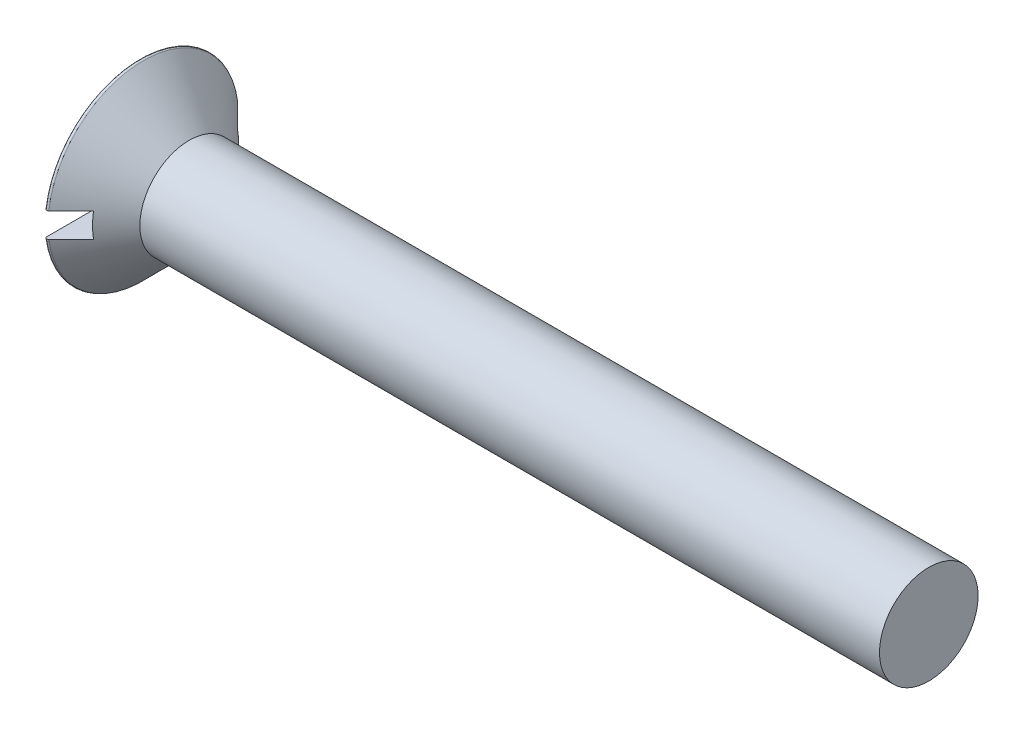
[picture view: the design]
ISO-10303-21;
HEADER;
FILE_DESCRIPTION(('STEP AP214'),'2;1');
FILE_NAME('part.step','',(''),(''),'','','');
FILE_SCHEMA(('AUTOMOTIVE_DESIGN { 1 0 10303 214 1 1 1 1 }'));
ENDSEC;
DATA;
#1=APPLICATION_CONTEXT('core data for automotive mechanical design processes');
#2=APPLICATION_PROTOCOL_DEFINITION('international standard','automotive_design',2000,#1);
#3=PRODUCT_CONTEXT('',#1,'mechanical');
#4=PRODUCT('Part','Part','',(#3));
#5=PRODUCT_RELATED_PRODUCT_CATEGORY('part','',(#4));
#6=PRODUCT_DEFINITION_FORMATION('','',#4);
#7=PRODUCT_DEFINITION_CONTEXT('part definition',#1,'design');
#8=PRODUCT_DEFINITION('design','',#6,#7);
#9=PRODUCT_DEFINITION_SHAPE('','',#8);
#10=(LENGTH_UNIT() NAMED_UNIT(*) SI_UNIT(.MILLI.,.METRE.));
#11=(NAMED_UNIT(*) PLANE_ANGLE_UNIT() SI_UNIT($,.RADIAN.));
#12=(NAMED_UNIT(*) SI_UNIT($,.STERADIAN.) SOLID_ANGLE_UNIT());
#13=UNCERTAINTY_MEASURE_WITH_UNIT(LENGTH_MEASURE(1.E-05),#10,'distance_accuracy_value','');
#14=(GEOMETRIC_REPRESENTATION_CONTEXT(3) GLOBAL_UNCERTAINTY_ASSIGNED_CONTEXT((#13)) GLOBAL_UNIT_ASSIGNED_CONTEXT((#10,
#11,#12)) REPRESENTATION_CONTEXT('',''));
#15=CARTESIAN_POINT('',(0.,0.,0.));
#16=DIRECTION('',(0.,0.,1.));
#17=DIRECTION('',(1.,0.,0.));
#18=AXIS2_PLACEMENT_3D('',#15,#16,#17);
#19=CARTESIAN_POINT('',(0.,0.,0.));
#20=DIRECTION('',(1.,0.,0.));
#21=DIRECTION('',(0.,0.,-1.));
#22=AXIS2_PLACEMENT_3D('',#19,#20,#21);
#23=PLANE('',#22);
#24=CARTESIAN_POINT('',(0.,0.,0.));
#25=DIRECTION('',(1.,0.,0.));
#26=DIRECTION('',(0.,0.,-1.));
#27=AXIS2_PLACEMENT_3D('',#24,#25,#26);
#28=CIRCLE('',#27,9.51715728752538);
#29=CARTESIAN_POINT('',(0.,1.25,9.4347115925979));
#30=VERTEX_POINT('',#29);
#31=CARTESIAN_POINT('',(0.,1.25,-9.43471159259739));
#32=VERTEX_POINT('',#31);
#33=EDGE_CURVE('E177',#30,#32,#28,.F.);
#34=ORIENTED_EDGE('',*,*,#33,.T.);
#35=DIRECTION('',(0.,0.,1.));
#36=VECTOR('',#35,1.);
#37=CARTESIAN_POINT('',(0.,1.25,-9.71715728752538));
#38=LINE('',#37,#36);
#39=EDGE_CURVE('E114',#32,#30,#38,.T.);
#40=ORIENTED_EDGE('',*,*,#39,.T.);
#41=EDGE_LOOP('',(#34,#40));
#42=FACE_BOUND('',#41,.T.);
#43=ADVANCED_FACE('F36',(#42),#23,.F.);
#44=CARTESIAN_POINT('',(0.2,0.,0.));
#45=DIRECTION('',(1.,0.,0.));
#46=DIRECTION('',(0.,0.,-1.));
#47=AXIS2_PLACEMENT_3D('',#44,#45,#46);
#48=TOROIDAL_SURFACE('',#47,9.51715728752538,0.2);
#49=CARTESIAN_POINT('',(0.0813932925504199,1.25,-9.59713064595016));
#50=CARTESIAN_POINT('',(0.090371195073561,1.25,-9.60379834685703));
#51=CARTESIAN_POINT('',(0.0999156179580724,1.25,-9.60971625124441));
#52=CARTESIAN_POINT('',(0.119869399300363,1.25,-9.61987230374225));
#53=CARTESIAN_POINT('',(0.130279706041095,1.25,-9.62410858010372));
#54=CARTESIAN_POINT('',(0.15166318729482,1.25,-9.63076900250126));
#55=CARTESIAN_POINT('',(0.162636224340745,1.25,-9.63319358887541));
#56=CARTESIAN_POINT('',(0.184831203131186,1.25,-9.63615852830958));
#57=CARTESIAN_POINT('',(0.196053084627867,1.25,-9.63669933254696));
#58=CARTESIAN_POINT('',(0.218392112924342,1.25,-9.63588331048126));
#59=CARTESIAN_POINT('',(0.229509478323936,1.25,-9.63453245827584));
#60=CARTESIAN_POINT('',(0.251359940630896,1.25,-9.62998393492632));
#61=CARTESIAN_POINT('',(0.262093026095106,1.25,-9.62678620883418));
#62=CARTESIAN_POINT('',(0.282875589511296,1.25,-9.61863708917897));
#63=CARTESIAN_POINT('',(0.292924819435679,1.25,-9.61368506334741));
#64=CARTESIAN_POINT('',(0.312055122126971,1.25,-9.60217267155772));
#65=CARTESIAN_POINT('',(0.321136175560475,1.25,-9.59561227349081));
#66=CARTESIAN_POINT('',(0.338125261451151,1.25,-9.58103410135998));
#67=CARTESIAN_POINT('',(0.34602683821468,1.25,-9.57300880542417));
#68=CARTESIAN_POINT('',(0.360383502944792,1.25,-9.55575484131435));
#69=CARTESIAN_POINT('',(0.36683853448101,1.25,-9.54652612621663));
#70=CARTESIAN_POINT('',(0.378174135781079,1.25,-9.52704814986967));
#71=CARTESIAN_POINT('',(0.383041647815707,1.25,-9.51679128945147));
#72=CARTESIAN_POINT('',(0.391000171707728,1.25,-9.49561008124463));
#73=CARTESIAN_POINT('',(0.394091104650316,1.25,-9.48468570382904));
#74=CARTESIAN_POINT('',(0.398430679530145,1.25,-9.46239224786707));
#75=CARTESIAN_POINT('',(0.399665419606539,1.25,-9.45102046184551));
#76=CARTESIAN_POINT('',(0.400215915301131,1.25,-9.42823040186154));
#77=CARTESIAN_POINT('',(0.399531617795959,1.25,-9.41681212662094));
#78=CARTESIAN_POINT('',(0.396256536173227,1.25,-9.39420937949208));
#79=CARTESIAN_POINT('',(0.393658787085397,1.25,-9.38302591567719));
#80=CARTESIAN_POINT('',(0.386619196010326,1.25,-9.36125501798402));
#81=CARTESIAN_POINT('',(0.382177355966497,1.25,-9.35066758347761));
#82=CARTESIAN_POINT('',(0.371581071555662,1.25,-9.3304129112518));
#83=CARTESIAN_POINT('',(0.365429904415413,1.25,-9.32074395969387));
#84=CARTESIAN_POINT('',(0.35158114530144,1.25,-9.30258514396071));
#85=CARTESIAN_POINT('',(0.343883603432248,1.25,-9.29409524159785));
#86=CARTESIAN_POINT('',(0.327215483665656,1.25,-9.2785990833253));
#87=CARTESIAN_POINT('',(0.318253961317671,1.25,-9.27158308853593));
#88=CARTESIAN_POINT('',(0.299271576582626,1.25,-9.25917099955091));
#89=CARTESIAN_POINT('',(0.289250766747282,1.25,-9.25377482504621));
#90=CARTESIAN_POINT('',(0.268528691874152,1.25,-9.24480504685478));
#91=CARTESIAN_POINT('',(0.257834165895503,1.25,-9.24121587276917));
#92=CARTESIAN_POINT('',(0.235992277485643,1.25,-9.23589752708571));
#93=CARTESIAN_POINT('',(0.224844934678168,1.25,-9.23416827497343));
#94=CARTESIAN_POINT('',(0.202493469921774,1.25,-9.23262729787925));
#95=CARTESIAN_POINT('',(0.191290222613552,1.25,-9.2328028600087));
#96=CARTESIAN_POINT('',(0.169072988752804,1.25,-9.23503550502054));
#97=CARTESIAN_POINT('',(0.158058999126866,1.25,-9.23709255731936));
#98=CARTESIAN_POINT('',(0.136548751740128,1.25,-9.24302213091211));
#99=CARTESIAN_POINT('',(0.126051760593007,1.25,-9.24689199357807));
#100=CARTESIAN_POINT('',(0.105852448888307,1.25,-9.25633161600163));
#101=CARTESIAN_POINT('',(0.096150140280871,1.25,-9.26190140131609));
#102=CARTESIAN_POINT('',(0.0777682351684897,1.25,-9.27460622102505));
#103=CARTESIAN_POINT('',(0.0690933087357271,1.25,-9.28174801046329));
#104=CARTESIAN_POINT('',(0.0530534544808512,1.25,-9.2973758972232));
#105=CARTESIAN_POINT('',(0.0456885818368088,1.25,-9.30586205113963));
#106=CARTESIAN_POINT('',(0.0324133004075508,1.25,-9.32401149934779));
#107=CARTESIAN_POINT('',(0.026515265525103,1.25,-9.33368384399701));
#108=CARTESIAN_POINT('',(0.016411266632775,1.25,-9.35387523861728));
#109=CARTESIAN_POINT('',(0.0122053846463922,1.25,-9.36439432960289));
#110=CARTESIAN_POINT('',(0.00557032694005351,1.25,-9.38607414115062));
#111=CARTESIAN_POINT('',(0.00315614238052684,1.25,-9.39723945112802));
#112=CARTESIAN_POINT('',(0.000226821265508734,1.25,-9.41981615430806));
#113=CARTESIAN_POINT('',(-0.000288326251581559,1.25,-9.43122754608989));
#114=CARTESIAN_POINT('',(0.000596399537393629,1.25,-9.45402874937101));
#115=CARTESIAN_POINT('',(0.00200510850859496,1.25,-9.46541821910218));
#116=CARTESIAN_POINT('',(0.00671661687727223,1.25,-9.48780185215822));
#117=CARTESIAN_POINT('',(0.010019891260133,1.25,-9.49879591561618));
#118=CARTESIAN_POINT('',(0.0184290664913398,1.25,-9.5200665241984));
#119=CARTESIAN_POINT('',(0.0235343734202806,1.25,-9.53034330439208));
#120=CARTESIAN_POINT('',(0.0354046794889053,1.25,-9.54987753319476));
#121=CARTESIAN_POINT('',(0.042167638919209,1.25,-9.5591362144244));
#122=CARTESIAN_POINT('',(0.0544013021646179,1.25,-9.57319981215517));
#123=CARTESIAN_POINT('',(0.0594345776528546,1.25,-9.57839171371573));
#124=CARTESIAN_POINT('',(0.0700308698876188,1.25,-9.58820358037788));
#125=CARTESIAN_POINT('',(0.0755938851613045,1.25,-9.59282354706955));
#126=CARTESIAN_POINT('',(0.0813932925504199,1.25,-9.59713064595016));
#127=B_SPLINE_CURVE_WITH_KNOTS('',3,(#49,#50,#51,#52,#53,#54,#55,#56,#57,#58,#59,#60,#61,#62,
#63,#64,#65,#66,#67,#68,#69,#70,#71,#72,#73,#74,#75,#76,#77,#78,#79,#80,#81,#82,#83,#84,#85,#86,
#87,#88,#89,#90,#91,#92,#93,#94,#95,#96,#97,#98,#99,#100,#101,#102,#103,#104,#105,#106,#107,
#108,#109,#110,#111,#112,#113,#114,#115,#116,#117,#118,#119,#120,#121,#122,#123,#124,#125,#126),
.UNSPECIFIED.,.T.,.F.,(4,2,2,2,2,2,2,2,2,2,2,2,2,2,2,2,2,2,2,2,2,2,2,2,2,2,2,2,2,2,2,2,2,2,2,2,
2,2,4),(0.,0.033523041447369,0.0670832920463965,0.100635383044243,0.134179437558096,
0.167617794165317,0.201057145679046,0.234508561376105,0.267960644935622,0.301589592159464,
0.335219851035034,0.369120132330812,0.40302191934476,0.437176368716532,0.471331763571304,
0.505612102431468,0.539892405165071,0.57410743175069,0.608321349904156,0.64230154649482,
0.676280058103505,0.70996054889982,0.74363958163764,0.777093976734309,0.810547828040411,
0.843952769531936,0.877358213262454,0.910910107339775,0.944463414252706,0.978290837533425,
1.01211990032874,1.04622891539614,1.08033773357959,1.11460373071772,1.14887832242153,
1.18314162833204,1.217362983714,1.23901774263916,1.26067244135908),.UNSPECIFIED.);
#128=CARTESIAN_POINT('',(0.341421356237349,1.25,-9.57735043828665));
#129=VERTEX_POINT('',#128);
#130=EDGE_CURVE('E60',#32,#129,#127,.T.);
#131=ORIENTED_EDGE('',*,*,#130,.F.);
#132=ORIENTED_EDGE('',*,*,#33,.F.);
#133=CARTESIAN_POINT('',(0.0799210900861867,1.25,9.27334894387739));
#134=CARTESIAN_POINT('',(0.0888343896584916,1.25,9.26659717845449));
#135=CARTESIAN_POINT('',(0.0983208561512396,1.25,9.26058928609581));
#136=CARTESIAN_POINT('',(0.118174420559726,1.25,9.2502444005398));
#137=CARTESIAN_POINT('',(0.12854247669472,1.25,9.24590925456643));
#138=CARTESIAN_POINT('',(0.149859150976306,1.25,9.23904565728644));
#139=CARTESIAN_POINT('',(0.160807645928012,1.25,9.23651682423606));
#140=CARTESIAN_POINT('',(0.182971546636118,1.25,9.23334179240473));
#141=CARTESIAN_POINT('',(0.194186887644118,1.25,9.23269514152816));
#142=CARTESIAN_POINT('',(0.216525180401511,1.25,9.23330134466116));
#143=CARTESIAN_POINT('',(0.227648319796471,1.25,9.23454730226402));
#144=CARTESIAN_POINT('',(0.249527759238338,1.25,9.23888874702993));
#145=CARTESIAN_POINT('',(0.260284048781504,1.25,9.24198428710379));
#146=CARTESIAN_POINT('',(0.281128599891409,1.25,9.24993372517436));
#147=CARTESIAN_POINT('',(0.291216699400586,1.25,9.25478804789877));
#148=CARTESIAN_POINT('',(0.310441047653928,1.25,9.26611211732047));
#149=CARTESIAN_POINT('',(0.319577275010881,1.25,9.27258190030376));
#150=CARTESIAN_POINT('',(0.336696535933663,1.25,9.28699118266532));
#151=CARTESIAN_POINT('',(0.344672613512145,1.25,9.294938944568));
#152=CARTESIAN_POINT('',(0.35919109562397,1.25,9.31205065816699));
#153=CARTESIAN_POINT('',(0.36573343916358,1.25,9.32121466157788));
#154=CARTESIAN_POINT('',(0.377258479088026,1.25,9.34058307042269));
#155=CARTESIAN_POINT('',(0.382227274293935,1.25,9.35079574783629));
#156=CARTESIAN_POINT('',(0.390394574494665,1.25,9.37190601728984));
#157=CARTESIAN_POINT('',(0.393592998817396,1.25,9.38280364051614));
#158=CARTESIAN_POINT('',(0.398151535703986,1.25,9.40506307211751));
#159=CARTESIAN_POINT('',(0.399497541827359,1.25,9.41642777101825));
#160=CARTESIAN_POINT('',(0.400269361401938,1.25,9.43922233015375));
#161=CARTESIAN_POINT('',(0.399695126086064,1.25,9.45065219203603));
#162=CARTESIAN_POINT('',(0.396636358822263,1.25,9.4732915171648));
#163=CARTESIAN_POINT('',(0.394145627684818,1.25,9.4845001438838));
#164=CARTESIAN_POINT('',(0.387313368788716,1.25,9.50633861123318));
#165=CARTESIAN_POINT('',(0.382971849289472,1.25,9.51696845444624));
#166=CARTESIAN_POINT('',(0.372568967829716,1.25,9.53731857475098));
#167=CARTESIAN_POINT('',(0.366511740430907,1.25,9.54704096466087));
#168=CARTESIAN_POINT('',(0.352840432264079,1.25,9.5653217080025));
#169=CARTESIAN_POINT('',(0.345226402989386,1.25,9.57388009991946));
#170=CARTESIAN_POINT('',(0.32871236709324,1.25,9.58952603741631));
#171=CARTESIAN_POINT('',(0.319821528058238,1.25,9.59662325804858));
#172=CARTESIAN_POINT('',(0.300966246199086,1.25,9.60920952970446));
#173=CARTESIAN_POINT('',(0.29100185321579,1.25,9.6146986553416));
#174=CARTESIAN_POINT('',(0.270370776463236,1.25,9.62386569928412));
#175=CARTESIAN_POINT('',(0.259710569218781,1.25,9.62755819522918));
#176=CARTESIAN_POINT('',(0.237919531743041,1.25,9.6330886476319));
#177=CARTESIAN_POINT('',(0.226788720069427,1.25,9.63492667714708));
#178=CARTESIAN_POINT('',(0.204445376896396,1.25,9.63668751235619));
#179=CARTESIAN_POINT('',(0.193233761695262,1.25,9.63662196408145));
#180=CARTESIAN_POINT('',(0.170981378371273,1.25,9.63460642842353));
#181=CARTESIAN_POINT('',(0.159940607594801,1.25,9.6326564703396));
#182=CARTESIAN_POINT('',(0.138359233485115,1.25,9.62693444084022));
#183=CARTESIAN_POINT('',(0.127817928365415,1.25,9.62316501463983));
#184=CARTESIAN_POINT('',(0.107514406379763,1.25,9.61391638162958));
#185=CARTESIAN_POINT('',(0.0977521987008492,1.25,9.60843715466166));
#186=CARTESIAN_POINT('',(0.0792428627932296,1.25,9.59590488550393));
#187=CARTESIAN_POINT('',(0.0704997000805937,1.25,9.5888459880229));
#188=CARTESIAN_POINT('',(0.0543116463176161,1.25,9.57337038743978));
#189=CARTESIAN_POINT('',(0.0468668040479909,1.25,9.56495363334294));
#190=CARTESIAN_POINT('',(0.0334270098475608,1.25,9.54693495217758));
#191=CARTESIAN_POINT('',(0.0274432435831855,1.25,9.5373246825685));
#192=CARTESIAN_POINT('',(0.01715908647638,1.25,9.51724214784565));
#193=CARTESIAN_POINT('',(0.01285877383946,1.25,9.50676984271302));
#194=CARTESIAN_POINT('',(0.00602839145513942,1.25,9.48516991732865));
#195=CARTESIAN_POINT('',(0.0035128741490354,1.25,9.47403769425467));
#196=CARTESIAN_POINT('',(0.000375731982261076,1.25,9.45150985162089));
#197=CARTESIAN_POINT('',(-0.000245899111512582,1.25,9.4401142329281));
#198=CARTESIAN_POINT('',(0.00042249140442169,1.25,9.41732033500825));
#199=CARTESIAN_POINT('',(0.00172236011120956,1.25,9.40592234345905));
#200=CARTESIAN_POINT('',(0.00621743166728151,1.25,9.38350300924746));
#201=CARTESIAN_POINT('',(0.00941311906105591,1.25,9.37248176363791));
#202=CARTESIAN_POINT('',(0.0176146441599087,1.25,9.35112891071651));
#203=CARTESIAN_POINT('',(0.022621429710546,1.25,9.34079766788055));
#204=CARTESIAN_POINT('',(0.0343046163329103,1.25,9.32113808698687));
#205=CARTESIAN_POINT('',(0.040978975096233,1.25,9.31180854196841));
#206=CARTESIAN_POINT('',(0.0530889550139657,1.25,9.29760515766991));
#207=CARTESIAN_POINT('',(0.0580845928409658,1.25,9.29234981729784));
#208=CARTESIAN_POINT('',(0.0686136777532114,1.25,9.28240858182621));
#209=CARTESIAN_POINT('',(0.0741471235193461,1.25,9.27772268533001));
#210=CARTESIAN_POINT('',(0.0799210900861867,1.25,9.27334894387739));
#211=B_SPLINE_CURVE_WITH_KNOTS('',3,(#133,#134,#135,#136,#137,#138,#139,#140,#141,#142,#143,
#144,#145,#146,#147,#148,#149,#150,#151,#152,#153,#154,#155,#156,#157,#158,#159,#160,#161,#162,
#163,#164,#165,#166,#167,#168,#169,#170,#171,#172,#173,#174,#175,#176,#177,#178,#179,#180,#181,
#182,#183,#184,#185,#186,#187,#188,#189,#190,#191,#192,#193,#194,#195,#196,#197,#198,#199,#200,
#201,#202,#203,#204,#205,#206,#207,#208,#209,#210),.UNSPECIFIED.,.T.,.F.,(4,2,2,2,2,2,2,2,2,2,2,
2,2,2,2,2,2,2,2,2,2,2,2,2,2,2,2,2,2,2,2,2,2,2,2,2,2,2,4),(0.,0.033519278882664,
0.0670754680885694,0.100624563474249,0.134165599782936,0.16758470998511,0.20100477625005,
0.234432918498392,0.267861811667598,0.301483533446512,0.335106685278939,0.369019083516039,
0.402933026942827,0.437103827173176,0.471275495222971,0.505558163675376,0.539840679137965,
0.574041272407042,0.608240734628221,0.642205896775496,0.676169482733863,0.709852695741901,
0.743534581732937,0.777010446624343,0.810485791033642,0.843912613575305,0.877339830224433,
0.910893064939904,0.944447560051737,0.978251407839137,1.01205682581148,1.04613480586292,
1.08021267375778,1.11446578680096,1.14872765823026,1.18300748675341,1.21724553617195,
1.23895911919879,1.26067264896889),.UNSPECIFIED.);
#212=CARTESIAN_POINT('',(0.341421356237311,1.25,9.57735043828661));
#213=VERTEX_POINT('',#212);
#214=EDGE_CURVE('E146',#213,#30,#211,.T.);
#215=ORIENTED_EDGE('',*,*,#214,.F.);
#216=CARTESIAN_POINT('',(0.341421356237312,0.,0.));
#217=DIRECTION('',(1.,0.,0.));
#218=DIRECTION('',(0.,0.,-1.));
#219=AXIS2_PLACEMENT_3D('',#216,#217,#218);
#220=CIRCLE('',#219,9.65857864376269);
#221=EDGE_CURVE('E179',#129,#213,#220,.T.);
#222=ORIENTED_EDGE('',*,*,#221,.F.);
#223=EDGE_LOOP('',(#131,#132,#215,#222));
#224=FACE_BOUND('',#223,.T.);
#225=ADVANCED_FACE('F159',(#224),#48,.T.);
#226=CARTESIAN_POINT('',(0.,-1.25,-9.43471159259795));
#227=VERTEX_POINT('',#226);
#228=CARTESIAN_POINT('',(0.,-1.25,9.4347115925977));
#229=VERTEX_POINT('',#228);
#230=EDGE_CURVE('E175',#227,#229,#28,.F.);
#231=ORIENTED_EDGE('',*,*,#230,.T.);
#232=DIRECTION('',(0.,0.,1.));
#233=VECTOR('',#232,1.);
#234=CARTESIAN_POINT('',(0.,-1.25,-9.71715728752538));
#235=LINE('',#234,#233);
#236=EDGE_CURVE('E52',#227,#229,#235,.T.);
#237=ORIENTED_EDGE('',*,*,#236,.F.);
#238=EDGE_LOOP('',(#231,#237));
#239=FACE_BOUND('',#238,.T.);
#240=ADVANCED_FACE('F161',(#239),#23,.F.);
#241=CARTESIAN_POINT('',(5.,0.,0.));
#242=DIRECTION('',(-1.,0.,0.));
#243=DIRECTION('',(0.,0.,1.));
#244=AXIS2_PLACEMENT_3D('',#241,#242,#243);
#245=CONICAL_SURFACE('',#244,4.99999999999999,0.785398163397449);
#246=CARTESIAN_POINT('',(2.6,0.,0.));
#247=DIRECTION('',(1.,0.,0.));
#248=DIRECTION('',(0.,0.,-1.));
#249=AXIS2_PLACEMENT_3D('',#246,#247,#248);
#250=CIRCLE('',#249,7.39999999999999);
#251=CARTESIAN_POINT('',(2.6,-1.25,-7.29366163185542));
#252=VERTEX_POINT('',#251);
#253=CARTESIAN_POINT('',(2.6,1.25,-7.29366163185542));
#254=VERTEX_POINT('',#253);
#255=EDGE_CURVE('E11',#252,#254,#250,.T.);
#256=ORIENTED_EDGE('',*,*,#255,.T.);
#257=CARTESIAN_POINT('',(-11.3280265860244,1.25,21.2913648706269));
#258=CARTESIAN_POINT('',(-10.6060390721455,1.25,20.5681248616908));
#259=CARTESIAN_POINT('',(-9.88410602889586,1.25,19.8448304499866));
#260=CARTESIAN_POINT('',(-8.44040761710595,1.25,18.3980557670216));
#261=CARTESIAN_POINT('',(-7.71864225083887,1.25,17.6745754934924));
#262=CARTESIAN_POINT('',(-6.27514974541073,1.25,16.2271633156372));
#263=CARTESIAN_POINT('',(-5.55342267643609,1.25,15.5032313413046));
#264=CARTESIAN_POINT('',(-4.11034955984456,1.25,14.055005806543));
#265=CARTESIAN_POINT('',(-3.38900350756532,1.25,13.3307122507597));
#266=CARTESIAN_POINT('',(-1.92001538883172,1.25,11.8545305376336));
#267=CARTESIAN_POINT('',(-1.1723955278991,1.25,11.1026202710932));
#268=CARTESIAN_POINT('',(-0.0518114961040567,1.25,9.97388579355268));
#269=CARTESIAN_POINT('',(0.321582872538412,1.25,9.5974887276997));
#270=CARTESIAN_POINT('',(1.06795908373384,1.25,8.84428853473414));
#271=CARTESIAN_POINT('',(1.44094092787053,1.25,8.46748540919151));
#272=CARTESIAN_POINT('',(2.18623226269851,1.25,7.7133507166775));
#273=CARTESIAN_POINT('',(2.55854186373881,1.25,7.33601925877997));
#274=CARTESIAN_POINT('',(3.30223496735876,1.25,6.5804325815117));
#275=CARTESIAN_POINT('',(3.673618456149,1.25,6.20217734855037));
#276=CARTESIAN_POINT('',(4.2294859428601,1.25,5.63363839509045));
#277=CARTESIAN_POINT('',(4.41456757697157,1.25,5.44393915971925));
#278=CARTESIAN_POINT('',(4.78418389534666,1.25,5.06400877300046));
#279=CARTESIAN_POINT('',(4.96871858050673,1.25,4.87377762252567));
#280=CARTESIAN_POINT('',(5.33702041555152,1.25,4.49258220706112));
#281=CARTESIAN_POINT('',(5.52078758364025,1.25,4.30161795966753));
#282=CARTESIAN_POINT('',(5.88721275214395,1.25,3.91862888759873));
#283=CARTESIAN_POINT('',(6.06987076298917,1.25,3.72660407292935));
#284=CARTESIAN_POINT('',(6.30050001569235,1.25,3.48196665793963));
#285=CARTESIAN_POINT('',(6.34927138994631,1.25,3.43010830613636));
#286=CARTESIAN_POINT('',(6.44666996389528,1.25,3.32625617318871));
#287=CARTESIAN_POINT('',(6.49529716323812,1.25,3.2742623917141));
#288=CARTESIAN_POINT('',(6.64093510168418,1.25,3.11805072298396));
#289=CARTESIAN_POINT('',(6.73770082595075,1.25,3.01360394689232));
#290=CARTESIAN_POINT('',(6.9300078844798,1.25,2.80429197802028));
#291=CARTESIAN_POINT('',(7.0255524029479,1.25,2.69942971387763));
#292=CARTESIAN_POINT('',(7.21545184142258,1.25,2.488636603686));
#293=CARTESIAN_POINT('',(7.30980680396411,1.25,2.38270579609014));
#294=CARTESIAN_POINT('',(7.46592798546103,1.25,2.20458548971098));
#295=CARTESIAN_POINT('',(7.52816410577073,1.25,2.13280834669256));
#296=CARTESIAN_POINT('',(7.65163425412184,1.25,1.98839825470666));
#297=CARTESIAN_POINT('',(7.71286830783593,1.25,1.91576532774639));
#298=CARTESIAN_POINT('',(7.83441388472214,1.25,1.76889150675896));
#299=CARTESIAN_POINT('',(7.89471627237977,1.25,1.694643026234));
#300=CARTESIAN_POINT('',(8.01344661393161,1.25,1.54466723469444));
#301=CARTESIAN_POINT('',(8.07187477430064,1.25,1.46894008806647));
#302=CARTESIAN_POINT('',(8.18685341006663,1.25,1.31442398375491));
#303=CARTESIAN_POINT('',(8.24336672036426,1.25,1.23560715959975));
#304=CARTESIAN_POINT('',(8.35236368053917,1.25,1.0750316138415));
#305=CARTESIAN_POINT('',(8.40484176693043,1.25,0.993269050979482));
#306=CARTESIAN_POINT('',(8.50285231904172,1.25,0.826718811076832));
#307=CARTESIAN_POINT('',(8.5484490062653,1.25,0.74196957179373));
#308=CARTESIAN_POINT('',(8.62927889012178,1.25,0.567694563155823));
#309=CARTESIAN_POINT('',(8.66454518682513,1.25,0.478185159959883));
#310=CARTESIAN_POINT('',(8.70411437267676,1.25,0.344144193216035));
#311=CARTESIAN_POINT('',(8.71484133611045,1.25,0.301515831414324));
#312=CARTESIAN_POINT('',(8.73227124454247,1.25,0.215431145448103));
#313=CARTESIAN_POINT('',(8.73897472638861,1.25,0.171974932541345));
#314=CARTESIAN_POINT('',(8.74787380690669,1.25,0.0847941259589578));
#315=CARTESIAN_POINT('',(8.75008975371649,1.25,0.0410716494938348));
#316=CARTESIAN_POINT('',(8.74990464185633,1.25,-0.0463652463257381));
#317=CARTESIAN_POINT('',(8.74750341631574,1.25,-0.0900796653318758));
#318=CARTESIAN_POINT('',(8.73829481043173,1.25,-0.176773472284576));
#319=CARTESIAN_POINT('',(8.73151321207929,1.25,-0.219755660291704));
#320=CARTESIAN_POINT('',(8.71402368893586,1.25,-0.304917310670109));
#321=CARTESIAN_POINT('',(8.70331409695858,1.25,-0.34709642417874));
#322=CARTESIAN_POINT('',(8.67848330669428,1.25,-0.430711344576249));
#323=CARTESIAN_POINT('',(8.66434111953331,1.25,-0.472140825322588));
#324=CARTESIAN_POINT('',(8.63328728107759,1.25,-0.553925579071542));
#325=CARTESIAN_POINT('',(8.61637609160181,1.25,-0.594281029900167));
#326=CARTESIAN_POINT('',(8.56555621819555,1.25,-0.706628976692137));
#327=CARTESIAN_POINT('',(8.52907332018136,1.25,-0.777452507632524));
#328=CARTESIAN_POINT('',(8.45116395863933,1.25,-0.916349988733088));
#329=CARTESIAN_POINT('',(8.40973193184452,1.25,-0.984420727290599));
#330=CARTESIAN_POINT('',(8.32334091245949,1.25,-1.11862778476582));
#331=CARTESIAN_POINT('',(8.27836928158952,1.25,-1.18475589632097));
#332=CARTESIAN_POINT('',(8.18606760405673,1.25,-1.31528541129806));
#333=CARTESIAN_POINT('',(8.13873861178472,1.25,-1.37968756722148));
#334=CARTESIAN_POINT('',(8.04188566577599,1.25,-1.50780806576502));
#335=CARTESIAN_POINT('',(7.99234474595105,1.25,-1.57151352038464));
#336=CARTESIAN_POINT('',(7.8919538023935,1.25,-1.69788985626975));
#337=CARTESIAN_POINT('',(7.8411036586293,1.25,-1.76056064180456));
#338=CARTESIAN_POINT('',(7.73853306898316,1.25,-1.88493129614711));
#339=CARTESIAN_POINT('',(7.68681500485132,1.25,-1.94663313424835));
#340=CARTESIAN_POINT('',(7.58260951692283,1.25,-2.06937786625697));
#341=CARTESIAN_POINT('',(7.53012212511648,1.25,-2.13042078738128));
#342=CARTESIAN_POINT('',(7.3739868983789,1.25,-2.3101825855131));
#343=CARTESIAN_POINT('',(7.26947966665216,1.25,-2.42815450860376));
#344=CARTESIAN_POINT('',(7.05892552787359,1.25,-2.66271846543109));
#345=CARTESIAN_POINT('',(6.95287855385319,1.25,-2.77931043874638));
#346=CARTESIAN_POINT('',(6.73969084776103,1.25,-3.01151685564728));
#347=CARTESIAN_POINT('',(6.63254997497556,1.25,-3.12713116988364));
#348=CARTESIAN_POINT('',(6.41748084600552,1.25,-3.3576256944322));
#349=CARTESIAN_POINT('',(6.30955258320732,1.25,-3.47250589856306));
#350=CARTESIAN_POINT('',(5.98463826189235,1.25,-3.81659421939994));
#351=CARTESIAN_POINT('',(5.76677689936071,1.25,-4.04497527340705));
#352=CARTESIAN_POINT('',(5.329679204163,1.25,-4.50037983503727));
#353=CARTESIAN_POINT('',(5.11044297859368,1.25,-4.72740344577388));
#354=CARTESIAN_POINT('',(4.67330000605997,1.25,-5.17824684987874));
#355=CARTESIAN_POINT('',(4.45540256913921,1.25,-5.40207567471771));
#356=CARTESIAN_POINT('',(4.01898567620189,1.25,-5.84913431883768));
#357=CARTESIAN_POINT('',(3.80046620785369,1.25,-6.07236412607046));
#358=CARTESIAN_POINT('',(3.36308799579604,1.25,-6.51828084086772));
#359=CARTESIAN_POINT('',(3.14422946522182,1.25,-6.74096795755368));
#360=CARTESIAN_POINT('',(2.70618245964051,1.25,-7.18601458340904));
#361=CARTESIAN_POINT('',(2.48699398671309,1.25,-7.40837409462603));
#362=CARTESIAN_POINT('',(1.70874703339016,1.25,-8.19700441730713));
#363=CARTESIAN_POINT('',(1.14901103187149,1.25,-8.76260650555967));
#364=CARTESIAN_POINT('',(0.0286677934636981,1.25,-9.89294962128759));
#365=CARTESIAN_POINT('',(-0.531939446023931,1.25,-10.4576906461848));
#366=CARTESIAN_POINT('',(-1.65380883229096,1.25,-11.5867514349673));
#367=CARTESIAN_POINT('',(-2.21507108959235,1.25,-12.1510710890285));
#368=CARTESIAN_POINT('',(-3.33794764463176,1.25,-13.2793588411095));
#369=CARTESIAN_POINT('',(-3.89956194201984,1.25,-13.8433269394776));
#370=CARTESIAN_POINT('',(-5.03323955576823,1.25,-14.9812633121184));
#371=CARTESIAN_POINT('',(-5.60530734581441,1.25,-15.5552271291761));
#372=CARTESIAN_POINT('',(-6.74962397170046,1.25,-16.7029746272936));
#373=CARTESIAN_POINT('',(-7.32187280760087,1.25,-17.2767583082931));
#374=CARTESIAN_POINT('',(-8.46638157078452,1.25,-18.4240701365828));
#375=CARTESIAN_POINT('',(-9.03864146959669,1.25,-18.9975983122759));
#376=CARTESIAN_POINT('',(-10.1832642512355,1.25,-20.1445514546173));
#377=CARTESIAN_POINT('',(-10.7556271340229,1.25,-20.7179764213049));
#378=CARTESIAN_POINT('',(-11.3280265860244,1.25,-21.2913648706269));
#379=B_SPLINE_CURVE_WITH_KNOTS('',3,(#257,#258,#259,#260,#261,#262,#263,#264,#265,#266,#267,
#268,#269,#270,#271,#272,#273,#274,#275,#276,#277,#278,#279,#280,#281,#282,#283,#284,#285,#286,
#287,#288,#289,#290,#291,#292,#293,#294,#295,#296,#297,#298,#299,#300,#301,#302,#303,#304,#305,
#306,#307,#308,#309,#310,#311,#312,#313,#314,#315,#316,#317,#318,#319,#320,#321,#322,#323,#324,
#325,#326,#327,#328,#329,#330,#331,#332,#333,#334,#335,#336,#337,#338,#339,#340,#341,#342,#343,
#344,#345,#346,#347,#348,#349,#350,#351,#352,#353,#354,#355,#356,#357,#358,#359,#360,#361,#362,
#363,#364,#365,#366,#367,#368,#369,#370,#371,#372,#373,#374,#375,#376,#377,#378),.UNSPECIFIED.,
.F.,.F.,(4,2,2,2,2,2,2,2,2,2,2,2,2,2,2,2,2,2,2,2,2,2,2,2,2,2,2,2,2,2,2,2,2,2,2,2,2,2,2,2,2,2,2,
2,2,2,2,2,2,2,2,2,2,2,2,2,2,2,2,2,4),(0.,3.0657917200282,6.13162282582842,9.1983322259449,
12.2650031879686,15.4459991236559,17.0365595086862,18.6271137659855,20.2173775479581,
21.8076648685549,22.6027547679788,23.3978433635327,24.1929129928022,24.9879751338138,
25.2015431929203,25.4151117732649,25.8422548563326,26.2678352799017,26.6934004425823,
26.9783983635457,27.2633889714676,27.5503225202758,27.8372243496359,28.1280957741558,
28.4193612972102,28.7077135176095,28.9951314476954,29.1268431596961,29.2585372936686,
29.3896329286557,29.5207333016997,29.6510689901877,29.7814600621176,29.9126694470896,
30.0438569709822,30.2825283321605,30.5214705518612,30.761308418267,31.0010399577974,
31.2431210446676,31.4852244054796,31.7267466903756,31.9682589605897,32.4410483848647,
32.9138584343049,33.3867300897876,33.859605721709,34.8064799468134,35.7532813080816,
36.6904068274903,37.6275510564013,38.5642455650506,39.500934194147,41.8881669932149,
44.2754069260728,46.6631352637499,49.0508612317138,51.4819646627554,53.9130689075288,
56.3436539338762,58.7742380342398),.UNSPECIFIED.);
#380=EDGE_CURVE('E112',#254,#129,#379,.T.);
#381=ORIENTED_EDGE('',*,*,#380,.T.);
#382=ORIENTED_EDGE('',*,*,#221,.T.);
#383=CARTESIAN_POINT('',(2.6,1.25,7.29366163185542));
#384=VERTEX_POINT('',#383);
#385=EDGE_CURVE('E109',#213,#384,#379,.T.);
#386=ORIENTED_EDGE('',*,*,#385,.T.);
#387=CARTESIAN_POINT('',(2.6,-1.25,7.29366163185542));
#388=VERTEX_POINT('',#387);
#389=EDGE_CURVE('E41',#384,#388,#250,.T.);
#390=ORIENTED_EDGE('',*,*,#389,.T.);
#391=CARTESIAN_POINT('',(-11.3280265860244,-1.25,-21.2913648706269));
#392=CARTESIAN_POINT('',(-10.6060390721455,-1.25,-20.5681248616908));
#393=CARTESIAN_POINT('',(-9.88410602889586,-1.25,-19.8448304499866));
#394=CARTESIAN_POINT('',(-8.44040761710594,-1.25,-18.3980557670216));
#395=CARTESIAN_POINT('',(-7.71864225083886,-1.25,-17.6745754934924));
#396=CARTESIAN_POINT('',(-6.27514974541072,-1.25,-16.2271633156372));
#397=CARTESIAN_POINT('',(-5.55342267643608,-1.25,-15.5032313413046));
#398=CARTESIAN_POINT('',(-4.11034955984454,-1.25,-14.055005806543));
#399=CARTESIAN_POINT('',(-3.38900350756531,-1.25,-13.3307122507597));
#400=CARTESIAN_POINT('',(-1.92001538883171,-1.25,-11.8545305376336));
#401=CARTESIAN_POINT('',(-1.17239552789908,-1.25,-11.1026202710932));
#402=CARTESIAN_POINT('',(-0.0518114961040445,-1.25,-9.97388579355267));
#403=CARTESIAN_POINT('',(0.321582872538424,-1.25,-9.59748872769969));
#404=CARTESIAN_POINT('',(1.06795908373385,-1.25,-8.84428853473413));
#405=CARTESIAN_POINT('',(1.44094092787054,-1.25,-8.4674854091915));
#406=CARTESIAN_POINT('',(2.18623226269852,-1.25,-7.71335071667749));
#407=CARTESIAN_POINT('',(2.55854186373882,-1.25,-7.33601925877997));
#408=CARTESIAN_POINT('',(3.30223496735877,-1.25,-6.58043258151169));
#409=CARTESIAN_POINT('',(3.67361845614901,-1.25,-6.20217734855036));
#410=CARTESIAN_POINT('',(4.22948594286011,-1.25,-5.63363839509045));
#411=CARTESIAN_POINT('',(4.41456757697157,-1.25,-5.44393915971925));
#412=CARTESIAN_POINT('',(4.78418389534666,-1.25,-5.06400877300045));
#413=CARTESIAN_POINT('',(4.96871858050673,-1.25,-4.87377762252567));
#414=CARTESIAN_POINT('',(5.33702041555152,-1.25,-4.49258220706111));
#415=CARTESIAN_POINT('',(5.52078758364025,-1.25,-4.30161795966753));
#416=CARTESIAN_POINT('',(5.88721275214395,-1.25,-3.91862888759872));
#417=CARTESIAN_POINT('',(6.06987076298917,-1.25,-3.72660407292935));
#418=CARTESIAN_POINT('',(6.30050001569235,-1.25,-3.48196665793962));
#419=CARTESIAN_POINT('',(6.34927138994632,-1.25,-3.43010830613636));
#420=CARTESIAN_POINT('',(6.44666996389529,-1.25,-3.3262561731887));
#421=CARTESIAN_POINT('',(6.49529716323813,-1.25,-3.27426239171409));
#422=CARTESIAN_POINT('',(6.64093510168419,-1.25,-3.11805072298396));
#423=CARTESIAN_POINT('',(6.73770082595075,-1.25,-3.01360394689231));
#424=CARTESIAN_POINT('',(6.9300078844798,-1.25,-2.80429197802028));
#425=CARTESIAN_POINT('',(7.0255524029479,-1.25,-2.69942971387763));
#426=CARTESIAN_POINT('',(7.21545184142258,-1.25,-2.488636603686));
#427=CARTESIAN_POINT('',(7.30980680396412,-1.25,-2.38270579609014));
#428=CARTESIAN_POINT('',(7.46592798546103,-1.25,-2.20458548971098));
#429=CARTESIAN_POINT('',(7.52816410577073,-1.25,-2.13280834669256));
#430=CARTESIAN_POINT('',(7.65163425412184,-1.25,-1.98839825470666));
#431=CARTESIAN_POINT('',(7.71286830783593,-1.25,-1.91576532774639));
#432=CARTESIAN_POINT('',(7.83441388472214,-1.25,-1.76889150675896));
#433=CARTESIAN_POINT('',(7.89471627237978,-1.25,-1.69464302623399));
#434=CARTESIAN_POINT('',(8.01344661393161,-1.25,-1.54466723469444));
#435=CARTESIAN_POINT('',(8.07187477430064,-1.25,-1.46894008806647));
#436=CARTESIAN_POINT('',(8.18685341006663,-1.25,-1.31442398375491));
#437=CARTESIAN_POINT('',(8.24336672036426,-1.25,-1.23560715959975));
#438=CARTESIAN_POINT('',(8.35236368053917,-1.25,-1.0750316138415));
#439=CARTESIAN_POINT('',(8.40484176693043,-1.25,-0.99326905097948));
#440=CARTESIAN_POINT('',(8.50285231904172,-1.25,-0.82671881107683));
#441=CARTESIAN_POINT('',(8.5484490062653,-1.25,-0.741969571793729));
#442=CARTESIAN_POINT('',(8.62927889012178,-1.25,-0.567694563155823));
#443=CARTESIAN_POINT('',(8.66454518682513,-1.25,-0.478185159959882));
#444=CARTESIAN_POINT('',(8.70411437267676,-1.25,-0.344144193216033));
#445=CARTESIAN_POINT('',(8.71484133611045,-1.25,-0.301515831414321));
#446=CARTESIAN_POINT('',(8.73227124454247,-1.25,-0.215431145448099));
#447=CARTESIAN_POINT('',(8.73897472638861,-1.25,-0.171974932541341));
#448=CARTESIAN_POINT('',(8.74787380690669,-1.25,-0.0847941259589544));
#449=CARTESIAN_POINT('',(8.75008975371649,-1.25,-0.0410716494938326));
#450=CARTESIAN_POINT('',(8.74990464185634,-1.25,0.046365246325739));
#451=CARTESIAN_POINT('',(8.74750341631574,-1.25,0.0900796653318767));
#452=CARTESIAN_POINT('',(8.73829481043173,-1.25,0.176773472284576));
#453=CARTESIAN_POINT('',(8.73151321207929,-1.25,0.219755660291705));
#454=CARTESIAN_POINT('',(8.71402368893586,-1.25,0.30491731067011));
#455=CARTESIAN_POINT('',(8.70331409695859,-1.25,0.347096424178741));
#456=CARTESIAN_POINT('',(8.67848330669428,-1.25,0.430711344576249));
#457=CARTESIAN_POINT('',(8.66434111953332,-1.25,0.472140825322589));
#458=CARTESIAN_POINT('',(8.63328728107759,-1.25,0.553925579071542));
#459=CARTESIAN_POINT('',(8.61637609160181,-1.25,0.594281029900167));
#460=CARTESIAN_POINT('',(8.56555621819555,-1.25,0.706628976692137));
#461=CARTESIAN_POINT('',(8.52907332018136,-1.25,0.777452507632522));
#462=CARTESIAN_POINT('',(8.45116395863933,-1.25,0.916349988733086));
#463=CARTESIAN_POINT('',(8.40973193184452,-1.25,0.984420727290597));
#464=CARTESIAN_POINT('',(8.32334091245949,-1.25,1.11862778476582));
#465=CARTESIAN_POINT('',(8.27836928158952,-1.25,1.18475589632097));
#466=CARTESIAN_POINT('',(8.18606760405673,-1.25,1.31528541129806));
#467=CARTESIAN_POINT('',(8.13873861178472,-1.25,1.37968756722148));
#468=CARTESIAN_POINT('',(8.04188566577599,-1.25,1.50780806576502));
#469=CARTESIAN_POINT('',(7.99234474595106,-1.25,1.57151352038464));
#470=CARTESIAN_POINT('',(7.8919538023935,-1.25,1.69788985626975));
#471=CARTESIAN_POINT('',(7.8411036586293,-1.25,1.76056064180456));
#472=CARTESIAN_POINT('',(7.73853306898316,-1.25,1.88493129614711));
#473=CARTESIAN_POINT('',(7.68681500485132,-1.25,1.94663313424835));
#474=CARTESIAN_POINT('',(7.58260951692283,-1.25,2.06937786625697));
#475=CARTESIAN_POINT('',(7.53012212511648,-1.25,2.13042078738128));
#476=CARTESIAN_POINT('',(7.3739868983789,-1.25,2.3101825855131));
#477=CARTESIAN_POINT('',(7.26947966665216,-1.25,2.42815450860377));
#478=CARTESIAN_POINT('',(7.05892552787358,-1.25,2.6627184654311));
#479=CARTESIAN_POINT('',(6.95287855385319,-1.25,2.77931043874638));
#480=CARTESIAN_POINT('',(6.73969084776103,-1.25,3.01151685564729));
#481=CARTESIAN_POINT('',(6.63254997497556,-1.25,3.12713116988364));
#482=CARTESIAN_POINT('',(6.41748084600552,-1.25,3.3576256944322));
#483=CARTESIAN_POINT('',(6.30955258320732,-1.25,3.47250589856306));
#484=CARTESIAN_POINT('',(5.98463826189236,-1.25,3.81659421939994));
#485=CARTESIAN_POINT('',(5.76677689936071,-1.25,4.04497527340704));
#486=CARTESIAN_POINT('',(5.329679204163,-1.25,4.50037983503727));
#487=CARTESIAN_POINT('',(5.11044297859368,-1.25,4.72740344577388));
#488=CARTESIAN_POINT('',(4.67330000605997,-1.25,5.17824684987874));
#489=CARTESIAN_POINT('',(4.45540256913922,-1.25,5.40207567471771));
#490=CARTESIAN_POINT('',(4.01898567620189,-1.25,5.84913431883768));
#491=CARTESIAN_POINT('',(3.80046620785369,-1.25,6.07236412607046));
#492=CARTESIAN_POINT('',(3.36308799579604,-1.25,6.51828084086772));
#493=CARTESIAN_POINT('',(3.14422946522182,-1.25,6.74096795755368));
#494=CARTESIAN_POINT('',(2.70618245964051,-1.25,7.18601458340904));
#495=CARTESIAN_POINT('',(2.48699398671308,-1.25,7.40837409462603));
#496=CARTESIAN_POINT('',(1.70874703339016,-1.25,8.19700441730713));
#497=CARTESIAN_POINT('',(1.14901103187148,-1.25,8.76260650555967));
#498=CARTESIAN_POINT('',(0.0286677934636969,-1.25,9.89294962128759));
#499=CARTESIAN_POINT('',(-0.531939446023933,-1.25,10.4576906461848));
#500=CARTESIAN_POINT('',(-1.65380883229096,-1.25,11.5867514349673));
#501=CARTESIAN_POINT('',(-2.21507108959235,-1.25,12.1510710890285));
#502=CARTESIAN_POINT('',(-3.33794764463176,-1.25,13.2793588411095));
#503=CARTESIAN_POINT('',(-3.89956194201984,-1.25,13.8433269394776));
#504=CARTESIAN_POINT('',(-5.03323955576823,-1.25,14.9812633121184));
#505=CARTESIAN_POINT('',(-5.60530734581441,-1.25,15.5552271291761));
#506=CARTESIAN_POINT('',(-6.74962397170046,-1.25,16.7029746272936));
#507=CARTESIAN_POINT('',(-7.32187280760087,-1.25,17.2767583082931));
#508=CARTESIAN_POINT('',(-8.46638157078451,-1.25,18.4240701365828));
#509=CARTESIAN_POINT('',(-9.03864146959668,-1.25,18.9975983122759));
#510=CARTESIAN_POINT('',(-10.1832642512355,-1.25,20.1445514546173));
#511=CARTESIAN_POINT('',(-10.7556271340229,-1.25,20.7179764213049));
#512=CARTESIAN_POINT('',(-11.3280265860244,-1.25,21.2913648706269));
#513=B_SPLINE_CURVE_WITH_KNOTS('',3,(#391,#392,#393,#394,#395,#396,#397,#398,#399,#400,#401,
#402,#403,#404,#405,#406,#407,#408,#409,#410,#411,#412,#413,#414,#415,#416,#417,#418,#419,#420,
#421,#422,#423,#424,#425,#426,#427,#428,#429,#430,#431,#432,#433,#434,#435,#436,#437,#438,#439,
#440,#441,#442,#443,#444,#445,#446,#447,#448,#449,#450,#451,#452,#453,#454,#455,#456,#457,#458,
#459,#460,#461,#462,#463,#464,#465,#466,#467,#468,#469,#470,#471,#472,#473,#474,#475,#476,#477,
#478,#479,#480,#481,#482,#483,#484,#485,#486,#487,#488,#489,#490,#491,#492,#493,#494,#495,#496,
#497,#498,#499,#500,#501,#502,#503,#504,#505,#506,#507,#508,#509,#510,#511,#512),.UNSPECIFIED.,
.F.,.F.,(4,2,2,2,2,2,2,2,2,2,2,2,2,2,2,2,2,2,2,2,2,2,2,2,2,2,2,2,2,2,2,2,2,2,2,2,2,2,2,2,2,2,2,
2,2,2,2,2,2,2,2,2,2,2,2,2,2,2,2,2,4),(0.,3.06579172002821,6.13162282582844,9.19833222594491,
12.2650031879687,15.4459991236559,17.0365595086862,18.6271137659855,20.2173775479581,
21.8076648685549,22.6027547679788,23.3978433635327,24.1929129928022,24.9879751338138,
25.2015431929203,25.4151117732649,25.8422548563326,26.2678352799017,26.6934004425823,
26.9783983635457,27.2633889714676,27.5503225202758,27.8372243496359,28.1280957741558,
28.4193612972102,28.7077135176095,28.9951314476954,29.1268431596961,29.2585372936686,
29.3896329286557,29.5207333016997,29.6510689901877,29.7814600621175,29.9126694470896,
30.0438569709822,30.2825283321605,30.5214705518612,30.761308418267,31.0010399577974,
31.2431210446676,31.4852244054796,31.7267466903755,31.9682589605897,32.4410483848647,
32.9138584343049,33.3867300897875,33.859605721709,34.8064799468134,35.7532813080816,
36.6904068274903,37.6275510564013,38.5642455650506,39.5009341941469,41.8881669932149,
44.2754069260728,46.6631352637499,49.0508612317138,51.4819646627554,53.9130689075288,
56.3436539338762,58.7742380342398),.UNSPECIFIED.);
#514=CARTESIAN_POINT('',(0.341421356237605,-1.25,9.57735043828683));
#515=VERTEX_POINT('',#514);
#516=EDGE_CURVE('E102',#388,#515,#513,.T.);
#517=ORIENTED_EDGE('',*,*,#516,.T.);
#518=CARTESIAN_POINT('',(0.341421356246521,-1.25,-9.57735043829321));
#519=VERTEX_POINT('',#518);
#520=EDGE_CURVE('E108',#515,#519,#220,.T.);
#521=ORIENTED_EDGE('',*,*,#520,.T.);
#522=EDGE_CURVE('E99',#519,#252,#513,.T.);
#523=ORIENTED_EDGE('',*,*,#522,.T.);
#524=EDGE_LOOP('',(#256,#381,#382,#386,#390,#517,#521,#523));
#525=FACE_BOUND('',#524,.T.);
#526=CARTESIAN_POINT('',(5.,0.,0.));
#527=DIRECTION('',(-1.,0.,0.));
#528=DIRECTION('',(0.,0.,1.));
#529=AXIS2_PLACEMENT_3D('',#526,#527,#528);
#530=CIRCLE('',#529,4.99999999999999);
#531=CARTESIAN_POINT('',(5.,0.,4.99999999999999));
#532=VERTEX_POINT('',#531);
#533=EDGE_CURVE('E180',#532,#532,#530,.T.);
#534=ORIENTED_EDGE('',*,*,#533,.T.);
#535=EDGE_LOOP('',(#534));
#536=FACE_BOUND('',#535,.T.);
#537=ADVANCED_FACE('F105',(#525,#536),#245,.T.);
#538=CARTESIAN_POINT('',(-5.56964084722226,0.,0.));
#539=DIRECTION('',(-1.,0.,0.));
#540=DIRECTION('',(0.,0.,1.));
#541=AXIS2_PLACEMENT_3D('',#538,#539,#540);
#542=CYLINDRICAL_SURFACE('',#541,4.99999999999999);
#543=ORIENTED_EDGE('',*,*,#533,.F.);
#544=EDGE_LOOP('',(#543));
#545=FACE_BOUND('',#544,.T.);
#546=CARTESIAN_POINT('',(80.,0.,0.));
#547=DIRECTION('',(-1.,0.,0.));
#548=DIRECTION('',(0.,0.,1.));
#549=AXIS2_PLACEMENT_3D('',#546,#547,#548);
#550=CIRCLE('',#549,5.);
#551=CARTESIAN_POINT('',(80.,0.,5.));
#552=VERTEX_POINT('',#551);
#553=EDGE_CURVE('E195',#552,#552,#550,.T.);
#554=ORIENTED_EDGE('',*,*,#553,.T.);
#555=EDGE_LOOP('',(#554));
#556=FACE_BOUND('',#555,.T.);
#557=ADVANCED_FACE('F172',(#545,#556),#542,.T.);
#558=CARTESIAN_POINT('',(80.,5.,0.));
#559=DIRECTION('',(-1.,0.,0.));
#560=DIRECTION('',(0.,0.,1.));
#561=AXIS2_PLACEMENT_3D('',#558,#559,#560);
#562=PLANE('',#561);
#563=ORIENTED_EDGE('',*,*,#553,.F.);
#564=EDGE_LOOP('',(#563));
#565=FACE_BOUND('',#564,.T.);
#566=ADVANCED_FACE('F133',(#565),#562,.F.);
#567=CARTESIAN_POINT('',(0.0813932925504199,-1.25,-9.59713064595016));
#568=CARTESIAN_POINT('',(0.0723141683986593,-1.25,-9.59038651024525));
#569=CARTESIAN_POINT('',(0.0638012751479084,-1.25,-9.58286555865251));
#570=CARTESIAN_POINT('',(0.0481550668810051,-1.25,-9.56649197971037));
#571=CARTESIAN_POINT('',(0.0410235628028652,-1.25,-9.55763763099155));
#572=CARTESIAN_POINT('',(0.0283503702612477,-1.25,-9.53886603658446));
#573=CARTESIAN_POINT('',(0.0228073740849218,-1.25,-9.52894967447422));
#574=CARTESIAN_POINT('',(0.0134555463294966,-1.25,-9.50833416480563));
#575=CARTESIAN_POINT('',(0.00964628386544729,-1.25,-9.49763521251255));
#576=CARTESIAN_POINT('',(0.00384385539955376,-1.25,-9.47568867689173));
#577=CARTESIAN_POINT('',(0.00186142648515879,-1.25,-9.46443825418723));
#578=CARTESIAN_POINT('',(-0.000196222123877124,-1.25,-9.44176373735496));
#579=CARTESIAN_POINT('',(-0.000271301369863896,-1.25,-9.43033963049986));
#580=CARTESIAN_POINT('',(0.00149178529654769,-1.25,-9.4075868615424));
#581=CARTESIAN_POINT('',(0.00333875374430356,-1.25,-9.396258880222));
#582=CARTESIAN_POINT('',(0.0089095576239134,-1.25,-9.37407399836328));
#583=CARTESIAN_POINT('',(0.0126333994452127,-1.25,-9.3632170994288));
#584=CARTESIAN_POINT('',(0.0218531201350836,-1.25,-9.34229340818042));
#585=CARTESIAN_POINT('',(0.0273476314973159,-1.25,-9.33222601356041));
#586=CARTESIAN_POINT('',(0.0399585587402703,-1.25,-9.3131639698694));
#587=CARTESIAN_POINT('',(0.0470749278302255,-1.25,-9.30416928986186));
#588=CARTESIAN_POINT('',(0.0626835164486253,-1.25,-9.287567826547));
#589=CARTESIAN_POINT('',(0.0711671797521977,-1.25,-9.27995300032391));
#590=CARTESIAN_POINT('',(0.0893021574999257,-1.25,-9.26627074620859));
#591=CARTESIAN_POINT('',(0.098953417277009,-1.25,-9.26020324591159));
#592=CARTESIAN_POINT('',(0.119059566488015,-1.25,-9.24984385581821));
#593=CARTESIAN_POINT('',(0.129506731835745,-1.25,-9.24553697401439));
#594=CARTESIAN_POINT('',(0.150979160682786,-1.25,-9.2387531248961));
#595=CARTESIAN_POINT('',(0.162004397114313,-1.25,-9.23627607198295));
#596=CARTESIAN_POINT('',(0.184232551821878,-1.25,-9.23323829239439));
#597=CARTESIAN_POINT('',(0.195433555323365,-1.25,-9.2326635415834));
#598=CARTESIAN_POINT('',(0.217772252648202,-1.25,-9.23340821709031));
#599=CARTESIAN_POINT('',(0.22890994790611,-1.25,-9.23472760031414));
#600=CARTESIAN_POINT('',(0.250775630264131,-1.25,-9.23921482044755));
#601=CARTESIAN_POINT('',(0.261504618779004,-1.25,-9.24237778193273));
#602=CARTESIAN_POINT('',(0.282281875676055,-1.25,-9.25045426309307));
#603=CARTESIAN_POINT('',(0.292330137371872,-1.25,-9.25536779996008));
#604=CARTESIAN_POINT('',(0.311498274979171,-1.25,-9.26682025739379));
#605=CARTESIAN_POINT('',(0.320614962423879,-1.25,-9.27336451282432));
#606=CARTESIAN_POINT('',(0.337630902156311,-1.25,-9.28787988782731));
#607=CARTESIAN_POINT('',(0.345530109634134,-1.25,-9.29585105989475));
#608=CARTESIAN_POINT('',(0.359952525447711,-1.25,-9.31305874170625));
#609=CARTESIAN_POINT('',(0.366464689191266,-1.25,-9.32230450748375));
#610=CARTESIAN_POINT('',(0.37785985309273,-1.25,-9.34175061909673));
#611=CARTESIAN_POINT('',(0.382742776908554,-1.25,-9.35195100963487));
#612=CARTESIAN_POINT('',(0.390783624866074,-1.25,-9.3731105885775));
#613=CARTESIAN_POINT('',(0.393926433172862,-1.25,-9.3840755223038));
#614=CARTESIAN_POINT('',(0.398338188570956,-1.25,-9.40637618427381));
#615=CARTESIAN_POINT('',(0.399607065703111,-1.25,-9.41771192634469));
#616=CARTESIAN_POINT('',(0.400238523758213,-1.25,-9.44050064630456));
#617=CARTESIAN_POINT('',(0.399590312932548,-1.25,-9.45195392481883));
#618=CARTESIAN_POINT('',(0.396381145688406,-1.25,-9.47458949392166));
#619=CARTESIAN_POINT('',(0.393820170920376,-1.25,-9.48577178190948));
#620=CARTESIAN_POINT('',(0.386853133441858,-1.25,-9.50755035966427));
#621=CARTESIAN_POINT('',(0.382446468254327,-1.25,-9.51814645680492));
#622=CARTESIAN_POINT('',(0.371908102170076,-1.25,-9.53844327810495));
#623=CARTESIAN_POINT('',(0.365776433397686,-1.25,-9.54814401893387));
#624=CARTESIAN_POINT('',(0.35199270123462,-1.25,-9.56632110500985));
#625=CARTESIAN_POINT('',(0.344348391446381,-1.25,-9.57480332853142));
#626=CARTESIAN_POINT('',(0.327733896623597,-1.25,-9.5903512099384));
#627=CARTESIAN_POINT('',(0.318763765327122,-1.25,-9.59741692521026));
#628=CARTESIAN_POINT('',(0.299829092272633,-1.25,-9.60987060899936));
#629=CARTESIAN_POINT('',(0.289873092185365,-1.25,-9.61527156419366));
#630=CARTESIAN_POINT('',(0.269191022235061,-1.25,-9.62431042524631));
#631=CARTESIAN_POINT('',(0.258465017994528,-1.25,-9.6279484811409));
#632=CARTESIAN_POINT('',(0.236635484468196,-1.25,-9.63333154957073));
#633=CARTESIAN_POINT('',(0.225535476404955,-1.25,-9.63509084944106));
#634=CARTESIAN_POINT('',(0.203194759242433,-1.25,-9.63671311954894));
#635=CARTESIAN_POINT('',(0.191954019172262,-1.25,-9.63657566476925));
#636=CARTESIAN_POINT('',(0.169695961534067,-1.25,-9.63441199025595));
#637=CARTESIAN_POINT('',(0.158678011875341,-1.25,-9.63239222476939));
#638=CARTESIAN_POINT('',(0.137146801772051,-1.25,-9.62653401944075));
#639=CARTESIAN_POINT('',(0.126632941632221,-1.25,-9.62269780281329));
#640=CARTESIAN_POINT('',(0.11032750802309,-1.25,-9.61514628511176));
#641=CARTESIAN_POINT('',(0.104284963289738,-1.25,-9.61196032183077));
#642=CARTESIAN_POINT('',(0.0925573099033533,-1.25,-9.60498741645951));
#643=CARTESIAN_POINT('',(0.0868722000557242,-1.25,-9.60120047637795));
#644=CARTESIAN_POINT('',(0.0813932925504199,-1.25,-9.59713064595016));
#645=B_SPLINE_CURVE_WITH_KNOTS('',3,(#567,#568,#569,#570,#571,#572,#573,#574,#575,#576,#577,
#578,#579,#580,#581,#582,#583,#584,#585,#586,#587,#588,#589,#590,#591,#592,#593,#594,#595,#596,
#597,#598,#599,#600,#601,#602,#603,#604,#605,#606,#607,#608,#609,#610,#611,#612,#613,#614,#615,
#616,#617,#618,#619,#620,#621,#622,#623,#624,#625,#626,#627,#628,#629,#630,#631,#632,#633,#634,
#635,#636,#637,#638,#639,#640,#641,#642,#643,#644),.UNSPECIFIED.,.T.,.F.,(4,2,2,2,2,2,2,2,2,2,2,
2,2,2,2,2,2,2,2,2,2,2,2,2,2,2,2,2,2,2,2,2,2,2,2,2,2,2,4),(0.,0.0339045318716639,
0.067853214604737,0.101773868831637,0.135686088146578,0.169796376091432,0.203909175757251,
0.238178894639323,0.272448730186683,0.306692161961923,0.340934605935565,0.374970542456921,
0.409004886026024,0.442743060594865,0.476479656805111,0.509966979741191,0.543453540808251,
0.576851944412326,0.61025067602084,0.64376013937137,0.677270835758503,0.711039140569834,
0.744809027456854,0.778867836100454,0.812927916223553,0.847180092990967,0.881432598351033,
0.915696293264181,0.949959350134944,0.984051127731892,1.01814152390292,1.05195882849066,
1.08577325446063,1.11932866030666,1.15289158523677,1.18633984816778,1.21974727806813,
1.24020744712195,1.26066754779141),.UNSPECIFIED.);
#646=EDGE_CURVE('E142',#519,#227,#645,.T.);
#647=ORIENTED_EDGE('',*,*,#646,.F.);
#648=ORIENTED_EDGE('',*,*,#520,.F.);
#649=CARTESIAN_POINT('',(0.0799210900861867,-1.25,9.27334894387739));
#650=CARTESIAN_POINT('',(0.0708989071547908,-1.25,9.28018445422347));
#651=CARTESIAN_POINT('',(0.0624509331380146,-1.25,9.28779227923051));
#652=CARTESIAN_POINT('',(0.0469482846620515,-1.25,9.30432755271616));
#653=CARTESIAN_POINT('',(0.039895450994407,-1.25,9.31325671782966));
#654=CARTESIAN_POINT('',(0.0273907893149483,-1.25,9.33216342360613));
#655=CARTESIAN_POINT('',(0.0219376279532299,-1.25,9.34214008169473));
#656=CARTESIAN_POINT('',(0.0127740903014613,-1.25,9.36286026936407));
#657=CARTESIAN_POINT('',(0.00906327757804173,-1.25,9.37360360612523));
#658=CARTESIAN_POINT('',(0.00346450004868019,-1.25,9.39562289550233));
#659=CARTESIAN_POINT('',(0.00158742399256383,-1.25,9.40690161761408));
#660=CARTESIAN_POINT('',(-0.000255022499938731,-1.25,9.42961476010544));
#661=CARTESIAN_POINT('',(-0.000220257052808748,-1.25,9.4410491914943));
#662=CARTESIAN_POINT('',(0.00176469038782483,-1.25,9.46379671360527));
#663=CARTESIAN_POINT('',(0.0037224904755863,-1.25,9.47510914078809));
#664=CARTESIAN_POINT('',(0.00951242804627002,-1.25,9.49724392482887));
#665=CARTESIAN_POINT('',(0.0133445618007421,-1.25,9.50806628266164));
#666=CARTESIAN_POINT('',(0.0227714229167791,-1.25,9.52889326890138));
#667=CARTESIAN_POINT('',(0.0283632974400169,-1.25,9.53889918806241));
#668=CARTESIAN_POINT('',(0.04115774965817,-1.25,9.55782221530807));
#669=CARTESIAN_POINT('',(0.0483602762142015,-1.25,9.56673935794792));
#670=CARTESIAN_POINT('',(0.064123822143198,-1.25,9.58316950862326));
#671=CARTESIAN_POINT('',(0.0726758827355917,-1.25,9.59069111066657));
#672=CARTESIAN_POINT('',(0.0909304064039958,-1.25,9.60417739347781));
#673=CARTESIAN_POINT('',(0.100632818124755,-1.25,9.61014214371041));
#674=CARTESIAN_POINT('',(0.120826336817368,-1.25,9.62029344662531));
#675=CARTESIAN_POINT('',(0.131310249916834,-1.25,9.62449431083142));
#676=CARTESIAN_POINT('',(0.152837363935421,-1.25,9.63106302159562));
#677=CARTESIAN_POINT('',(0.163880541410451,-1.25,9.63343094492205));
#678=CARTESIAN_POINT('',(0.186134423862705,-1.25,9.63625311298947));
#679=CARTESIAN_POINT('',(0.197343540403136,-1.25,9.63671989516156));
#680=CARTESIAN_POINT('',(0.219680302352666,-1.25,9.63576038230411));
#681=CARTESIAN_POINT('',(0.230807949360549,-1.25,9.63433412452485));
#682=CARTESIAN_POINT('',(0.252640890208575,-1.25,9.62963637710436));
#683=CARTESIAN_POINT('',(0.26334705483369,-1.25,9.62636893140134));
#684=CARTESIAN_POINT('',(0.284061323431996,-1.25,9.61808838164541));
#685=CARTESIAN_POINT('',(0.294069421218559,-1.25,9.61307526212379));
#686=CARTESIAN_POINT('',(0.313138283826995,-1.25,9.60143190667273));
#687=CARTESIAN_POINT('',(0.322196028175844,-1.25,9.59479672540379));
#688=CARTESIAN_POINT('',(0.339078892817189,-1.25,9.5801097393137));
#689=CARTESIAN_POINT('',(0.346903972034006,-1.25,9.57205788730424));
#690=CARTESIAN_POINT('',(0.361159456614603,-1.25,9.55470598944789));
#691=CARTESIAN_POINT('',(0.367579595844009,-1.25,9.54539751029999));
#692=CARTESIAN_POINT('',(0.378780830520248,-1.25,9.52584183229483));
#693=CARTESIAN_POINT('',(0.383561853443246,-1.25,9.51559459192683));
#694=CARTESIAN_POINT('',(0.391389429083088,-1.25,9.49436244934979));
#695=CARTESIAN_POINT('',(0.394421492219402,-1.25,9.48337220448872));
#696=CARTESIAN_POINT('',(0.398609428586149,-1.25,9.46103980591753));
#697=CARTESIAN_POINT('',(0.399765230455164,-1.25,9.44969763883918));
#698=CARTESIAN_POINT('',(0.400171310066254,-1.25,9.42691293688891));
#699=CARTESIAN_POINT('',(0.399410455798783,-1.25,9.41547020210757));
#700=CARTESIAN_POINT('',(0.395980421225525,-1.25,9.39287422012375));
#701=CARTESIAN_POINT('',(0.393311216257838,-1.25,9.38172097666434));
#702=CARTESIAN_POINT('',(0.386133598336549,-1.25,9.36001202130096));
#703=CARTESIAN_POINT('',(0.381623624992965,-1.25,9.34945682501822));
#704=CARTESIAN_POINT('',(0.370887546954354,-1.25,9.3292582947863));
#705=CARTESIAN_POINT('',(0.364661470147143,-1.25,9.31961494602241));
#706=CARTESIAN_POINT('',(0.350698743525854,-1.25,9.30156454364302));
#707=CARTESIAN_POINT('',(0.342969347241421,-1.25,9.29315188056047));
#708=CARTESIAN_POINT('',(0.326197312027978,-1.25,9.27775697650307));
#709=CARTESIAN_POINT('',(0.317154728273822,-1.25,9.27077467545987));
#710=CARTESIAN_POINT('',(0.298093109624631,-1.25,9.2585010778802));
#711=CARTESIAN_POINT('',(0.288082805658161,-1.25,9.25319622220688));
#712=CARTESIAN_POINT('',(0.267308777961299,-1.25,9.2443585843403));
#713=CARTESIAN_POINT('',(0.256545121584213,-1.25,9.24082564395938));
#714=CARTESIAN_POINT('',(0.234665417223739,-1.25,9.23566016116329));
#715=CARTESIAN_POINT('',(0.223553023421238,-1.25,9.2340121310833));
#716=CARTESIAN_POINT('',(0.201206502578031,-1.25,9.23261361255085));
#717=CARTESIAN_POINT('',(0.189972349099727,-1.25,9.23286354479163));
#718=CARTESIAN_POINT('',(0.16774996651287,-1.25,9.23524913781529));
#719=CARTESIAN_POINT('',(0.156760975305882,-1.25,9.23737774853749));
#720=CARTESIAN_POINT('',(0.135305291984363,-1.25,9.2434465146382));
#721=CARTESIAN_POINT('',(0.124837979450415,-1.25,9.24738445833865));
#722=CARTESIAN_POINT('',(0.108626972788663,-1.25,9.25508825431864));
#723=CARTESIAN_POINT('',(0.102627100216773,-1.25,9.25832737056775));
#724=CARTESIAN_POINT('',(0.0909891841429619,-1.25,9.26540072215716));
#725=CARTESIAN_POINT('',(0.0853511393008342,-1.25,9.26923495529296));
#726=CARTESIAN_POINT('',(0.0799210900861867,-1.25,9.27334894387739));
#727=B_SPLINE_CURVE_WITH_KNOTS('',3,(#649,#650,#651,#652,#653,#654,#655,#656,#657,#658,#659,
#660,#661,#662,#663,#664,#665,#666,#667,#668,#669,#670,#671,#672,#673,#674,#675,#676,#677,#678,
#679,#680,#681,#682,#683,#684,#685,#686,#687,#688,#689,#690,#691,#692,#693,#694,#695,#696,#697,
#698,#699,#700,#701,#702,#703,#704,#705,#706,#707,#708,#709,#710,#711,#712,#713,#714,#715,#716,
#717,#718,#719,#720,#721,#722,#723,#724,#725,#726),.UNSPECIFIED.,.T.,.F.,(4,2,2,2,2,2,2,2,2,2,2,
2,2,2,2,2,2,2,2,2,2,2,2,2,2,2,2,2,2,2,2,2,2,2,2,2,2,2,4),(0.,0.0339324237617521,
0.0679093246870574,0.101857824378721,0.135797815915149,0.169938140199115,0.204080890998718,
0.238359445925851,0.27263793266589,0.306861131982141,0.341083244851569,0.375087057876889,
0.409089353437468,0.442810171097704,0.476529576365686,0.510026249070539,0.543522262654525,
0.57694499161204,0.610368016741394,0.643894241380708,0.677421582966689,0.711186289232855,
0.744952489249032,0.778994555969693,0.813037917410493,0.847279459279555,0.881521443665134,
0.915792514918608,0.950063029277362,0.984172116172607,1.01827977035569,1.05210422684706,
1.08592566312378,1.11946715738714,1.15301608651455,1.18643965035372,1.21982246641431,
1.24024495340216,1.26066736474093),.UNSPECIFIED.);
#728=EDGE_CURVE('E137',#229,#515,#727,.T.);
#729=ORIENTED_EDGE('',*,*,#728,.F.);
#730=ORIENTED_EDGE('',*,*,#230,.F.);
#731=EDGE_LOOP('',(#647,#648,#729,#730));
#732=FACE_BOUND('',#731,.T.);
#733=ADVANCED_FACE('F38',(#732),#48,.T.);
#734=CARTESIAN_POINT('',(2.6,1.25,-9.71715728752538));
#735=DIRECTION('',(1.,0.,0.));
#736=DIRECTION('',(0.,0.,-1.));
#737=AXIS2_PLACEMENT_3D('',#734,#735,#736);
#738=PLANE('',#737);
#739=DIRECTION('',(0.,0.,1.));
#740=VECTOR('',#739,1.);
#741=CARTESIAN_POINT('',(2.6,1.25,-9.71715728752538));
#742=LINE('',#741,#740);
#743=EDGE_CURVE('E95',#254,#384,#742,.T.);
#744=ORIENTED_EDGE('',*,*,#743,.F.);
#745=ORIENTED_EDGE('',*,*,#255,.F.);
#746=DIRECTION('',(0.,0.,1.));
#747=VECTOR('',#746,1.);
#748=CARTESIAN_POINT('',(2.6,-1.25,-9.71715728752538));
#749=LINE('',#748,#747);
#750=EDGE_CURVE('E92',#252,#388,#749,.T.);
#751=ORIENTED_EDGE('',*,*,#750,.T.);
#752=ORIENTED_EDGE('',*,*,#389,.F.);
#753=EDGE_LOOP('',(#744,#745,#751,#752));
#754=FACE_BOUND('',#753,.T.);
#755=ADVANCED_FACE('F91',(#754),#738,.F.);
#756=CARTESIAN_POINT('',(0.,1.25,-9.71715728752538));
#757=DIRECTION('',(0.,1.,0.));
#758=DIRECTION('',(-1.,0.,0.));
#759=AXIS2_PLACEMENT_3D('',#756,#757,#758);
#760=PLANE('',#759);
#761=ORIENTED_EDGE('',*,*,#743,.T.);
#762=ORIENTED_EDGE('',*,*,#385,.F.);
#763=ORIENTED_EDGE('',*,*,#214,.T.);
#764=ORIENTED_EDGE('',*,*,#39,.F.);
#765=ORIENTED_EDGE('',*,*,#130,.T.);
#766=ORIENTED_EDGE('',*,*,#380,.F.);
#767=EDGE_LOOP('',(#761,#762,#763,#764,#765,#766));
#768=FACE_BOUND('',#767,.T.);
#769=ADVANCED_FACE('F132',(#768),#760,.F.);
#770=CARTESIAN_POINT('',(0.,-1.25,-9.71715728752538));
#771=DIRECTION('',(0.,-1.,0.));
#772=DIRECTION('',(0.,0.,-1.));
#773=AXIS2_PLACEMENT_3D('',#770,#771,#772);
#774=PLANE('',#773);
#775=ORIENTED_EDGE('',*,*,#646,.T.);
#776=ORIENTED_EDGE('',*,*,#236,.T.);
#777=ORIENTED_EDGE('',*,*,#728,.T.);
#778=ORIENTED_EDGE('',*,*,#516,.F.);
#779=ORIENTED_EDGE('',*,*,#750,.F.);
#780=ORIENTED_EDGE('',*,*,#522,.F.);
#781=EDGE_LOOP('',(#775,#776,#777,#778,#779,#780));
#782=FACE_BOUND('',#781,.T.);
#783=ADVANCED_FACE('F98',(#782),#774,.F.);
#784=CLOSED_SHELL('',(#43,#225,#240,#537,#557,#566,#733,#755,#769,#783));
#785=MANIFOLD_SOLID_BREP('B2',#784);
#786=ADVANCED_BREP_SHAPE_REPRESENTATION('',(#18,#785),#14);
#787=SHAPE_DEFINITION_REPRESENTATION(#9,#786);
ENDSEC;
END-ISO-10303-21;
